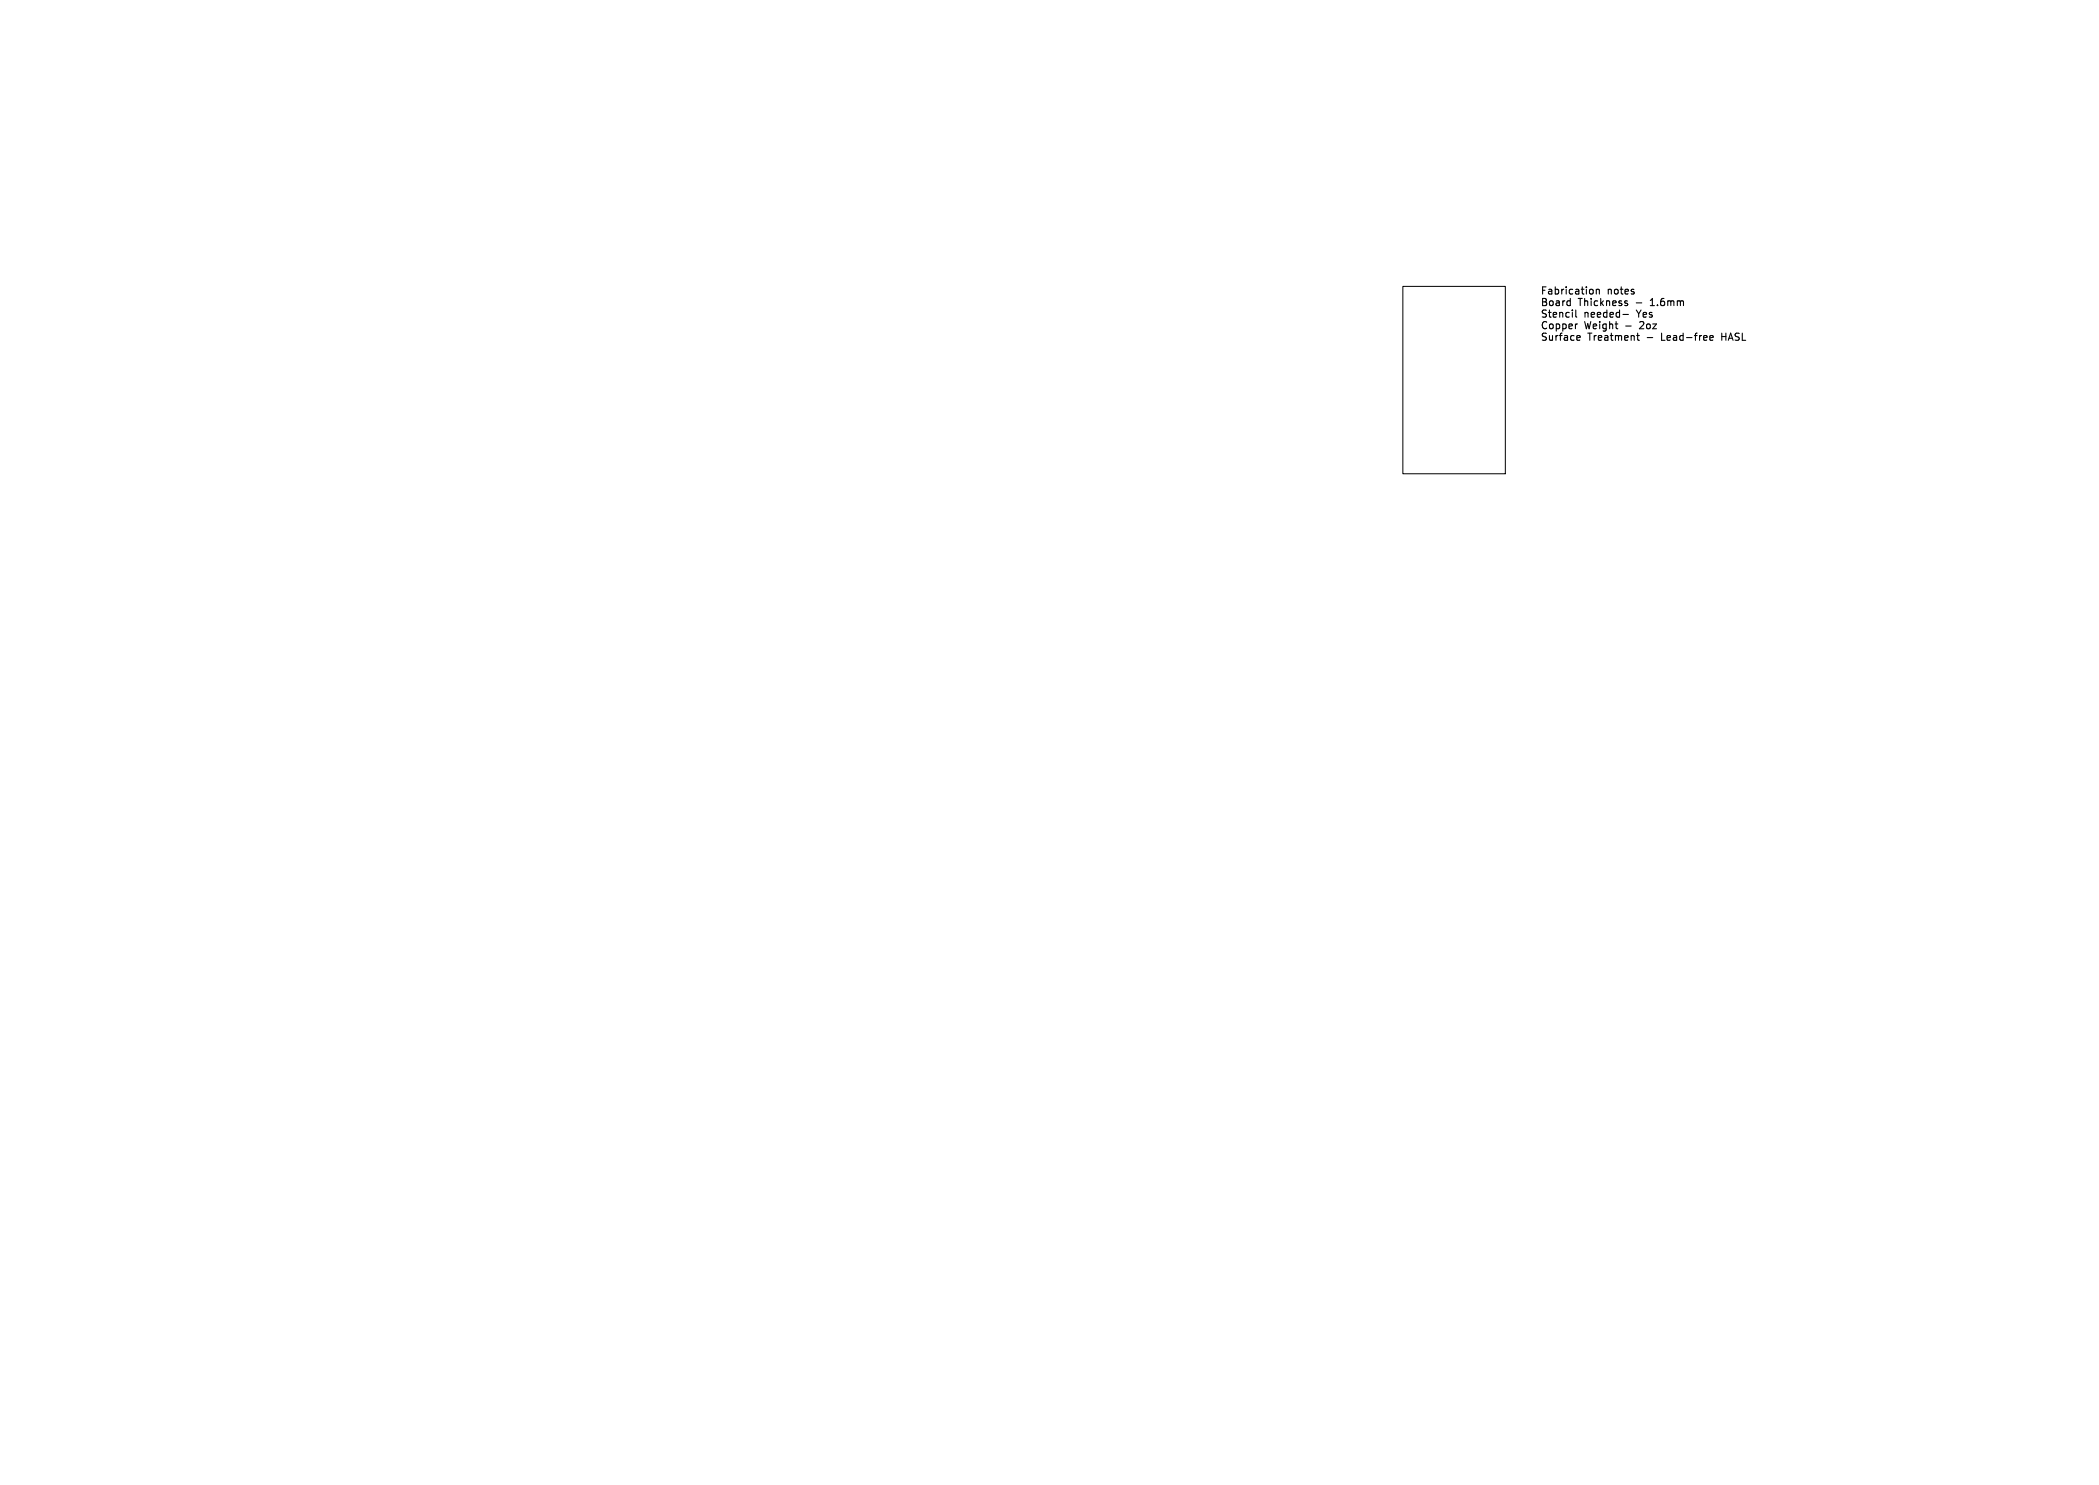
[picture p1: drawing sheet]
<svg xmlns="http://www.w3.org/2000/svg" width="297mm" height="210mm" viewBox="0 0 297 210" stroke-linecap="round" stroke-linejoin="round" font-family="sans-serif">
<defs><g id="words">
<g font-size="1.4">
<text x="217.9" y="41.7">Fabrication</text>
<text x="227.5" y="41.7">notes</text>
<text x="217.9" y="43.4">Board</text>
<text x="217.9" y="45">Stencil</text>
<text x="217.9" y="46.6">Copper</text>
<text x="223.4" y="43.4">Thickness</text>
<text x="224.2" y="45">needed-</text>
<text x="224.2" y="46.6">Weight</text>
<text x="230.2" y="46.6">-</text>
<text x="231.7" y="43.4">-</text>
<text x="231.8" y="45">Yes</text>
<text x="232.5" y="46.6">2oz</text>
<text x="234" y="43.4">1.6mm</text>
<text x="217.9" y="48.3">Surface</text>
<text x="224.7" y="48.3">Treatment</text>
<text x="233.2" y="48.3">-</text>
<text x="235.5" y="48.3">Lead-free</text>
<text x="244.3" y="48.3">HASL</text>
</g>
</g></defs>
<g fill="none" stroke="#000" stroke-width=".15">
<path d="M222.1 42.5l.1 .1M222.2 42.2v1M222.2 43.2h-.1M223 43.8v.9l.1 .2M223.2 48.1h.3M223.2 47.5h.3l.1 .2-.5 .1M223.2 45.8l-.2 .1M225.2 40.9l.2 .2v.3l-.2 .2M225.9 41l.1-.1 .3 .1v.6M225.9 40.9v.7M229.6 44.5h.8M230.2 42.9l.1 .1-.1 .2"/>
<path d="M230.2 42.5l.1 .1M231.6 47.5h.4M231.7 47.1v.9l.3 .1M232.1 45.5l-.1 .1M232.5 45.9l-.5 .6h.6M233.5 43.2h.6M233.7 42.3l-.2 .2M235.1 47.1v1h.5M242 48.1h.4M242 47.5h.3l.1 .2-.5 .1M243.6 47.1v1M243.6 47.6h.6"/>
</g>
<path d="M198.5 40.5h14.5v26.5h-14.5z" fill="none" stroke="#000" stroke-width=".14"/>
<use href="#words"/>
</svg>
